VERSION 5.7 ;
BUSBITCHARS "[]" ;
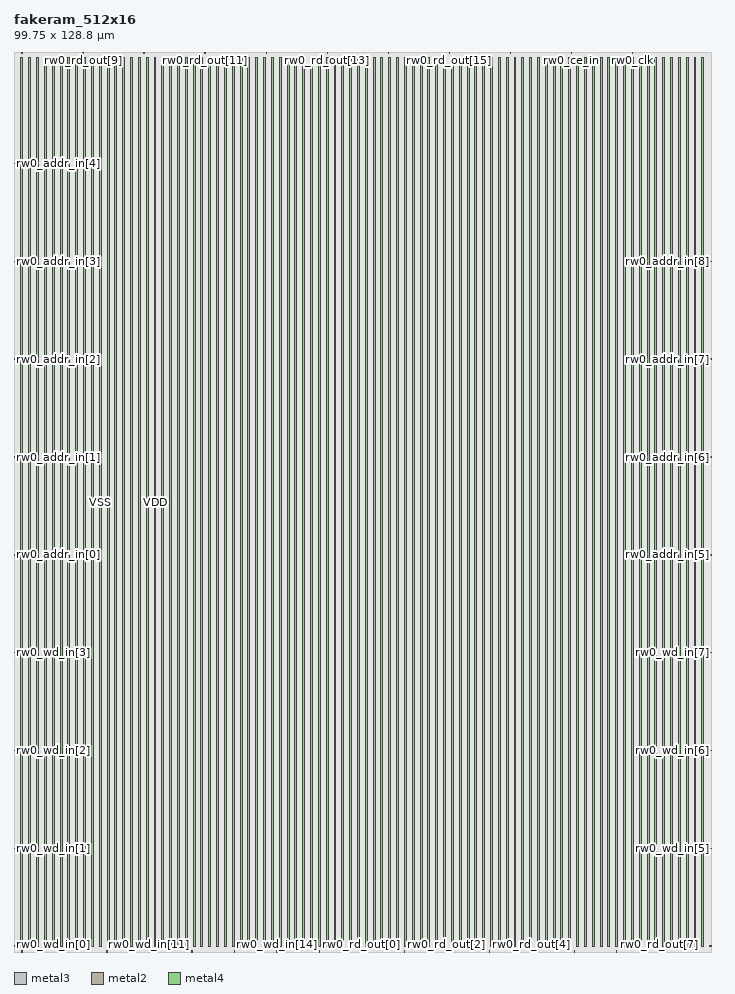
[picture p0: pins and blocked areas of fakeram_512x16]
MACRO fakeram_512x16
  FOREIGN fakeram_512x16 0 0 ;
  SYMMETRY X Y R90 ;
  SIZE 99.750 BY 128.800 ;
  CLASS BLOCK ;
  PIN rw0_wd_in[0]
    DIRECTION INPUT ;
    USE SIGNAL ;
    SHAPE ABUTMENT ;
    PORT
      LAYER metal3 ;
      RECT 0.000 0.805 0.210 0.875 ;
    END
  END rw0_wd_in[0]
  PIN rw0_wd_in[1]
    DIRECTION INPUT ;
    USE SIGNAL ;
    SHAPE ABUTMENT ;
    PORT
      LAYER metal3 ;
      RECT 0.000 14.805 0.210 14.875 ;
    END
  END rw0_wd_in[1]
  PIN rw0_wd_in[2]
    DIRECTION INPUT ;
    USE SIGNAL ;
    SHAPE ABUTMENT ;
    PORT
      LAYER metal3 ;
      RECT 0.000 28.805 0.210 28.875 ;
    END
  END rw0_wd_in[2]
  PIN rw0_wd_in[3]
    DIRECTION INPUT ;
    USE SIGNAL ;
    SHAPE ABUTMENT ;
    PORT
      LAYER metal3 ;
      RECT 0.000 42.805 0.210 42.875 ;
    END
  END rw0_wd_in[3]
  PIN rw0_wd_in[4]
    DIRECTION INPUT ;
    USE SIGNAL ;
    SHAPE ABUTMENT ;
    PORT
      LAYER metal3 ;
      RECT 99.540 0.805 99.750 0.875 ;
    END
  END rw0_wd_in[4]
  PIN rw0_wd_in[5]
    DIRECTION INPUT ;
    USE SIGNAL ;
    SHAPE ABUTMENT ;
    PORT
      LAYER metal3 ;
      RECT 99.540 14.805 99.750 14.875 ;
    END
  END rw0_wd_in[5]
  PIN rw0_wd_in[6]
    DIRECTION INPUT ;
    USE SIGNAL ;
    SHAPE ABUTMENT ;
    PORT
      LAYER metal3 ;
      RECT 99.540 28.805 99.750 28.875 ;
    END
  END rw0_wd_in[6]
  PIN rw0_wd_in[7]
    DIRECTION INPUT ;
    USE SIGNAL ;
    SHAPE ABUTMENT ;
    PORT
      LAYER metal3 ;
      RECT 99.540 42.805 99.750 42.875 ;
    END
  END rw0_wd_in[7]
  PIN rw0_wd_in[8]
    DIRECTION INPUT ;
    USE SIGNAL ;
    SHAPE ABUTMENT ;
    PORT
      LAYER metal2 ;
      RECT 1.105 0.000 1.175 0.210 ;
    END
  END rw0_wd_in[8]
  PIN rw0_wd_in[9]
    DIRECTION INPUT ;
    USE SIGNAL ;
    SHAPE ABUTMENT ;
    PORT
      LAYER metal2 ;
      RECT 7.185 0.000 7.255 0.210 ;
    END
  END rw0_wd_in[9]
  PIN rw0_wd_in[10]
    DIRECTION INPUT ;
    USE SIGNAL ;
    SHAPE ABUTMENT ;
    PORT
      LAYER metal2 ;
      RECT 13.265 0.000 13.335 0.210 ;
    END
  END rw0_wd_in[10]
  PIN rw0_wd_in[11]
    DIRECTION INPUT ;
    USE SIGNAL ;
    SHAPE ABUTMENT ;
    PORT
      LAYER metal2 ;
      RECT 19.345 0.000 19.415 0.210 ;
    END
  END rw0_wd_in[11]
  PIN rw0_wd_in[12]
    DIRECTION INPUT ;
    USE SIGNAL ;
    SHAPE ABUTMENT ;
    PORT
      LAYER metal2 ;
      RECT 25.425 0.000 25.495 0.210 ;
    END
  END rw0_wd_in[12]
  PIN rw0_wd_in[13]
    DIRECTION INPUT ;
    USE SIGNAL ;
    SHAPE ABUTMENT ;
    PORT
      LAYER metal2 ;
      RECT 31.505 0.000 31.575 0.210 ;
    END
  END rw0_wd_in[13]
  PIN rw0_wd_in[14]
    DIRECTION INPUT ;
    USE SIGNAL ;
    SHAPE ABUTMENT ;
    PORT
      LAYER metal2 ;
      RECT 37.585 0.000 37.655 0.210 ;
    END
  END rw0_wd_in[14]
  PIN rw0_wd_in[15]
    DIRECTION INPUT ;
    USE SIGNAL ;
    SHAPE ABUTMENT ;
    PORT
      LAYER metal2 ;
      RECT 43.665 0.000 43.735 0.210 ;
    END
  END rw0_wd_in[15]
  PIN rw0_rd_out[0]
    DIRECTION OUTPUT ;
    USE SIGNAL ;
    SHAPE ABUTMENT ;
    PORT
      LAYER metal2 ;
      RECT 49.745 0.000 49.815 0.210 ;
    END
  END rw0_rd_out[0]
  PIN rw0_rd_out[1]
    DIRECTION OUTPUT ;
    USE SIGNAL ;
    SHAPE ABUTMENT ;
    PORT
      LAYER metal2 ;
      RECT 55.825 0.000 55.895 0.210 ;
    END
  END rw0_rd_out[1]
  PIN rw0_rd_out[2]
    DIRECTION OUTPUT ;
    USE SIGNAL ;
    SHAPE ABUTMENT ;
    PORT
      LAYER metal2 ;
      RECT 61.905 0.000 61.975 0.210 ;
    END
  END rw0_rd_out[2]
  PIN rw0_rd_out[3]
    DIRECTION OUTPUT ;
    USE SIGNAL ;
    SHAPE ABUTMENT ;
    PORT
      LAYER metal2 ;
      RECT 67.985 0.000 68.055 0.210 ;
    END
  END rw0_rd_out[3]
  PIN rw0_rd_out[4]
    DIRECTION OUTPUT ;
    USE SIGNAL ;
    SHAPE ABUTMENT ;
    PORT
      LAYER metal2 ;
      RECT 74.065 0.000 74.135 0.210 ;
    END
  END rw0_rd_out[4]
  PIN rw0_rd_out[5]
    DIRECTION OUTPUT ;
    USE SIGNAL ;
    SHAPE ABUTMENT ;
    PORT
      LAYER metal2 ;
      RECT 80.145 0.000 80.215 0.210 ;
    END
  END rw0_rd_out[5]
  PIN rw0_rd_out[6]
    DIRECTION OUTPUT ;
    USE SIGNAL ;
    SHAPE ABUTMENT ;
    PORT
      LAYER metal2 ;
      RECT 86.225 0.000 86.295 0.210 ;
    END
  END rw0_rd_out[6]
  PIN rw0_rd_out[7]
    DIRECTION OUTPUT ;
    USE SIGNAL ;
    SHAPE ABUTMENT ;
    PORT
      LAYER metal2 ;
      RECT 92.305 0.000 92.375 0.210 ;
    END
  END rw0_rd_out[7]
  PIN rw0_rd_out[8]
    DIRECTION OUTPUT ;
    USE SIGNAL ;
    SHAPE ABUTMENT ;
    PORT
      LAYER metal2 ;
      RECT 1.105 128.590 1.175 128.800 ;
    END
  END rw0_rd_out[8]
  PIN rw0_rd_out[9]
    DIRECTION OUTPUT ;
    USE SIGNAL ;
    SHAPE ABUTMENT ;
    PORT
      LAYER metal2 ;
      RECT 9.845 128.590 9.915 128.800 ;
    END
  END rw0_rd_out[9]
  PIN rw0_rd_out[10]
    DIRECTION OUTPUT ;
    USE SIGNAL ;
    SHAPE ABUTMENT ;
    PORT
      LAYER metal2 ;
      RECT 18.585 128.590 18.655 128.800 ;
    END
  END rw0_rd_out[10]
  PIN rw0_rd_out[11]
    DIRECTION OUTPUT ;
    USE SIGNAL ;
    SHAPE ABUTMENT ;
    PORT
      LAYER metal2 ;
      RECT 27.325 128.590 27.395 128.800 ;
    END
  END rw0_rd_out[11]
  PIN rw0_rd_out[12]
    DIRECTION OUTPUT ;
    USE SIGNAL ;
    SHAPE ABUTMENT ;
    PORT
      LAYER metal2 ;
      RECT 36.065 128.590 36.135 128.800 ;
    END
  END rw0_rd_out[12]
  PIN rw0_rd_out[13]
    DIRECTION OUTPUT ;
    USE SIGNAL ;
    SHAPE ABUTMENT ;
    PORT
      LAYER metal2 ;
      RECT 44.805 128.590 44.875 128.800 ;
    END
  END rw0_rd_out[13]
  PIN rw0_rd_out[14]
    DIRECTION OUTPUT ;
    USE SIGNAL ;
    SHAPE ABUTMENT ;
    PORT
      LAYER metal2 ;
      RECT 53.545 128.590 53.615 128.800 ;
    END
  END rw0_rd_out[14]
  PIN rw0_rd_out[15]
    DIRECTION OUTPUT ;
    USE SIGNAL ;
    SHAPE ABUTMENT ;
    PORT
      LAYER metal2 ;
      RECT 62.285 128.590 62.355 128.800 ;
    END
  END rw0_rd_out[15]
  PIN rw0_addr_in[0]
    DIRECTION INPUT ;
    USE SIGNAL ;
    SHAPE ABUTMENT ;
    PORT
      LAYER metal3 ;
      RECT 0.000 56.805 0.210 56.875 ;
    END
  END rw0_addr_in[0]
  PIN rw0_addr_in[1]
    DIRECTION INPUT ;
    USE SIGNAL ;
    SHAPE ABUTMENT ;
    PORT
      LAYER metal3 ;
      RECT 0.000 70.805 0.210 70.875 ;
    END
  END rw0_addr_in[1]
  PIN rw0_addr_in[2]
    DIRECTION INPUT ;
    USE SIGNAL ;
    SHAPE ABUTMENT ;
    PORT
      LAYER metal3 ;
      RECT 0.000 84.805 0.210 84.875 ;
    END
  END rw0_addr_in[2]
  PIN rw0_addr_in[3]
    DIRECTION INPUT ;
    USE SIGNAL ;
    SHAPE ABUTMENT ;
    PORT
      LAYER metal3 ;
      RECT 0.000 98.805 0.210 98.875 ;
    END
  END rw0_addr_in[3]
  PIN rw0_addr_in[4]
    DIRECTION INPUT ;
    USE SIGNAL ;
    SHAPE ABUTMENT ;
    PORT
      LAYER metal3 ;
      RECT 0.000 112.805 0.210 112.875 ;
    END
  END rw0_addr_in[4]
  PIN rw0_addr_in[5]
    DIRECTION INPUT ;
    USE SIGNAL ;
    SHAPE ABUTMENT ;
    PORT
      LAYER metal3 ;
      RECT 99.540 56.805 99.750 56.875 ;
    END
  END rw0_addr_in[5]
  PIN rw0_addr_in[6]
    DIRECTION INPUT ;
    USE SIGNAL ;
    SHAPE ABUTMENT ;
    PORT
      LAYER metal3 ;
      RECT 99.540 70.805 99.750 70.875 ;
    END
  END rw0_addr_in[6]
  PIN rw0_addr_in[7]
    DIRECTION INPUT ;
    USE SIGNAL ;
    SHAPE ABUTMENT ;
    PORT
      LAYER metal3 ;
      RECT 99.540 84.805 99.750 84.875 ;
    END
  END rw0_addr_in[7]
  PIN rw0_addr_in[8]
    DIRECTION INPUT ;
    USE SIGNAL ;
    SHAPE ABUTMENT ;
    PORT
      LAYER metal3 ;
      RECT 99.540 98.805 99.750 98.875 ;
    END
  END rw0_addr_in[8]
  PIN rw0_we_in
    DIRECTION INPUT ;
    USE SIGNAL ;
    SHAPE ABUTMENT ;
    PORT
      LAYER metal2 ;
      RECT 71.025 128.590 71.095 128.800 ;
    END
  END rw0_we_in
  PIN rw0_ce_in
    DIRECTION INPUT ;
    USE SIGNAL ;
    SHAPE ABUTMENT ;
    PORT
      LAYER metal2 ;
      RECT 79.765 128.590 79.835 128.800 ;
    END
  END rw0_ce_in
  PIN rw0_clk
    DIRECTION INPUT ;
    USE SIGNAL ;
    SHAPE ABUTMENT ;
    PORT
      LAYER metal2 ;
      RECT 88.505 128.590 88.575 128.800 ;
    END
  END rw0_clk
  PIN VSS
    DIRECTION INOUT ;
    USE GROUND ;
    PORT
      LAYER metal4 ;
      RECT 1.000 0.840 1.280 127.960 ;
      RECT 3.240 0.840 3.520 127.960 ;
      RECT 5.480 0.840 5.760 127.960 ;
      RECT 7.720 0.840 8.000 127.960 ;
      RECT 9.960 0.840 10.240 127.960 ;
      RECT 12.200 0.840 12.480 127.960 ;
      RECT 14.440 0.840 14.720 127.960 ;
      RECT 16.680 0.840 16.960 127.960 ;
      RECT 18.920 0.840 19.200 127.960 ;
      RECT 21.160 0.840 21.440 127.960 ;
      RECT 23.400 0.840 23.680 127.960 ;
      RECT 25.640 0.840 25.920 127.960 ;
      RECT 27.880 0.840 28.160 127.960 ;
      RECT 30.120 0.840 30.400 127.960 ;
      RECT 32.360 0.840 32.640 127.960 ;
      RECT 34.600 0.840 34.880 127.960 ;
      RECT 36.840 0.840 37.120 127.960 ;
      RECT 39.080 0.840 39.360 127.960 ;
      RECT 41.320 0.840 41.600 127.960 ;
      RECT 43.560 0.840 43.840 127.960 ;
      RECT 45.800 0.840 46.080 127.960 ;
      RECT 48.040 0.840 48.320 127.960 ;
      RECT 50.280 0.840 50.560 127.960 ;
      RECT 52.520 0.840 52.800 127.960 ;
      RECT 54.760 0.840 55.040 127.960 ;
      RECT 57.000 0.840 57.280 127.960 ;
      RECT 59.240 0.840 59.520 127.960 ;
      RECT 61.480 0.840 61.760 127.960 ;
      RECT 63.720 0.840 64.000 127.960 ;
      RECT 65.960 0.840 66.240 127.960 ;
      RECT 68.200 0.840 68.480 127.960 ;
      RECT 70.440 0.840 70.720 127.960 ;
      RECT 72.680 0.840 72.960 127.960 ;
      RECT 74.920 0.840 75.200 127.960 ;
      RECT 77.160 0.840 77.440 127.960 ;
      RECT 79.400 0.840 79.680 127.960 ;
      RECT 81.640 0.840 81.920 127.960 ;
      RECT 83.880 0.840 84.160 127.960 ;
      RECT 86.120 0.840 86.400 127.960 ;
      RECT 88.360 0.840 88.640 127.960 ;
      RECT 90.600 0.840 90.880 127.960 ;
      RECT 92.840 0.840 93.120 127.960 ;
      RECT 95.080 0.840 95.360 127.960 ;
      RECT 97.320 0.840 97.600 127.960 ;
    END
  END VSS
  PIN VDD
    DIRECTION INOUT ;
    USE POWER ;
    PORT
      LAYER metal4 ;
      RECT 2.120 0.840 2.400 127.960 ;
      RECT 4.360 0.840 4.640 127.960 ;
      RECT 6.600 0.840 6.880 127.960 ;
      RECT 8.840 0.840 9.120 127.960 ;
      RECT 11.080 0.840 11.360 127.960 ;
      RECT 13.320 0.840 13.600 127.960 ;
      RECT 15.560 0.840 15.840 127.960 ;
      RECT 17.800 0.840 18.080 127.960 ;
      RECT 20.040 0.840 20.320 127.960 ;
      RECT 22.280 0.840 22.560 127.960 ;
      RECT 24.520 0.840 24.800 127.960 ;
      RECT 26.760 0.840 27.040 127.960 ;
      RECT 29.000 0.840 29.280 127.960 ;
      RECT 31.240 0.840 31.520 127.960 ;
      RECT 33.480 0.840 33.760 127.960 ;
      RECT 35.720 0.840 36.000 127.960 ;
      RECT 37.960 0.840 38.240 127.960 ;
      RECT 40.200 0.840 40.480 127.960 ;
      RECT 42.440 0.840 42.720 127.960 ;
      RECT 44.680 0.840 44.960 127.960 ;
      RECT 46.920 0.840 47.200 127.960 ;
      RECT 49.160 0.840 49.440 127.960 ;
      RECT 51.400 0.840 51.680 127.960 ;
      RECT 53.640 0.840 53.920 127.960 ;
      RECT 55.880 0.840 56.160 127.960 ;
      RECT 58.120 0.840 58.400 127.960 ;
      RECT 60.360 0.840 60.640 127.960 ;
      RECT 62.600 0.840 62.880 127.960 ;
      RECT 64.840 0.840 65.120 127.960 ;
      RECT 67.080 0.840 67.360 127.960 ;
      RECT 69.320 0.840 69.600 127.960 ;
      RECT 71.560 0.840 71.840 127.960 ;
      RECT 73.800 0.840 74.080 127.960 ;
      RECT 76.040 0.840 76.320 127.960 ;
      RECT 78.280 0.840 78.560 127.960 ;
      RECT 80.520 0.840 80.800 127.960 ;
      RECT 82.760 0.840 83.040 127.960 ;
      RECT 85.000 0.840 85.280 127.960 ;
      RECT 87.240 0.840 87.520 127.960 ;
      RECT 89.480 0.840 89.760 127.960 ;
      RECT 91.720 0.840 92.000 127.960 ;
      RECT 93.960 0.840 94.240 127.960 ;
      RECT 96.200 0.840 96.480 127.960 ;
      RECT 98.440 0.840 98.720 127.960 ;
    END
  END VDD
  OBS
    LAYER metal1 ;
    RECT 0 0 99.750 128.800 ;
    LAYER metal2 ;
    RECT 0 0 99.750 128.800 ;
    LAYER metal3 ;
    RECT 0 0 99.750 128.800 ;
    LAYER metal4 ;
    RECT 0 0 99.750 128.800 ;
    LAYER OVERLAP ;
    RECT 0 0 99.750 128.800 ;
  END
END fakeram_512x16

END LIBRARY
